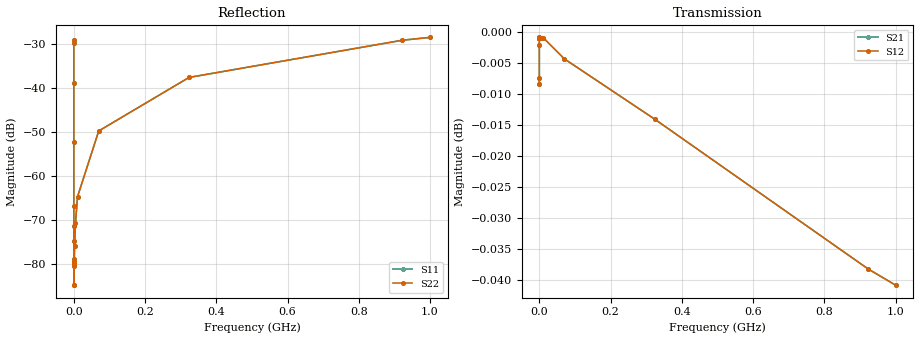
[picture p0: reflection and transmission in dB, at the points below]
!  *** S-Parameter ***
!  Copyright (C) Panasonic Industry Corporation
!  Conductive Polymer Aluminum Electrolytic Capacitor (SP-Cap)
!  Parts No. EEFHX0E471R9
!  Connection Mode : Series
!  1  o---||---o  2
!  GND o--------o GND
!  Conditions : Temperature = 20 degC , DC Bias = 0 V
! Frequency Range : 100Hz  -  1GHz  [ 401 Steps ]
# Hz S RI R 50
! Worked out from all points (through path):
!   401 points, 100 Hz to 1 GHz, reference 50 ohm
!   highest |S21| = 0.00 dB at 316.2 kHz (marker M1); lowest = 0.0 dB at 1 GHz (marker M2)
!   lowest |S11| = -84.9 dB at 258.5 kHz (marker M3), VSWR 1.00, Z = 50 + j0.000177 ohm
!   |S11| at or under -10 dB: start of sweep to end of sweep
!   |S22| runs from -84.9 to -28.4 dB; largest |S21 - S12| = 0
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100  0.00157 -0.0357  0.9984 0.0357  0.9984 0.0357  0.00157 -0.0357
108.3927  0.00137 -0.033  0.9986 0.033  0.9986 0.033  0.00137 -0.033
309.0295  0.000276 -0.0116  0.9997 0.0116  0.9997 0.0116  0.000276 -0.0116
1487.647  8.92e-05 -0.00244  0.9999 0.00244  0.9999 0.00244  8.92e-05 -0.00244
8081.649  6.96e-05 -0.000454  0.9999 0.000454  0.9999 0.000454  6.96e-05 -0.000454
14206.92  6.65e-05 -0.00026  0.9999 0.00026  0.9999 0.00026  6.65e-05 -0.00026
22130.95  6.47e-05 -0.000167  0.9999 0.000167  0.9999 0.000167  6.47e-05 -0.000167
38904.51  6.32e-05 -9.51e-05  0.9999 9.51e-05  0.9999 9.51e-05  6.32e-05 -9.51e-05
43903.59  6.28e-05 -8.41e-05  0.9999 8.41e-05  0.9999 8.41e-05  6.28e-05 -8.41e-05
49545.02  6.25e-05 -7.43e-05  0.9999 7.43e-05  0.9999 7.43e-05  6.25e-05 -7.43e-05
258523.5  5.69e-05 1.77e-06  0.9999 -1.77e-06  0.9999 -1.77e-06  5.69e-05 1.77e-06
316227.8  5.68e-05 9.14e-06  0.9999 -9.14e-06  0.9999 -9.14e-06  5.68e-05 9.14e-06
1017419  6.32e-05 6.88e-05  0.9999 -6.88e-05  0.9999 -6.88e-05  6.32e-05 6.88e-05
1148154  6.51e-05 7.78e-05  0.9999 -7.78e-05  0.9999 -7.78e-05  6.51e-05 7.78e-05
1244515  6.65e-05 8.43e-05  0.9999 -8.43e-05  0.9999 -8.43e-05  6.65e-05 8.43e-05
2101358  7.89e-05 0.000136  0.9999 -0.000136  0.9999 -0.000136  7.89e-05 0.000136
4704354  0.000103 0.000272  0.9999 -0.000272  0.9999 -0.000272  0.000103 0.000272
1.053174e7  0.000139 0.000564  0.9999 -0.000564  0.9999 -0.000564  0.000139 0.000564
6.99842e7  0.000466 0.00323  0.9995 -0.00323  0.9995 -0.00323  0.000466 0.00323
3.235937e8  0.00167 0.0132  0.9983 -0.0132  0.9983 -0.0132  0.00167 0.0132
9.225714e8  0.00495 0.035  0.995 -0.035  0.995 -0.035  0.00495 0.035
1e9  0.0054 0.0377  0.9946 -0.0377  0.9946 -0.0377  0.0054 0.0377
